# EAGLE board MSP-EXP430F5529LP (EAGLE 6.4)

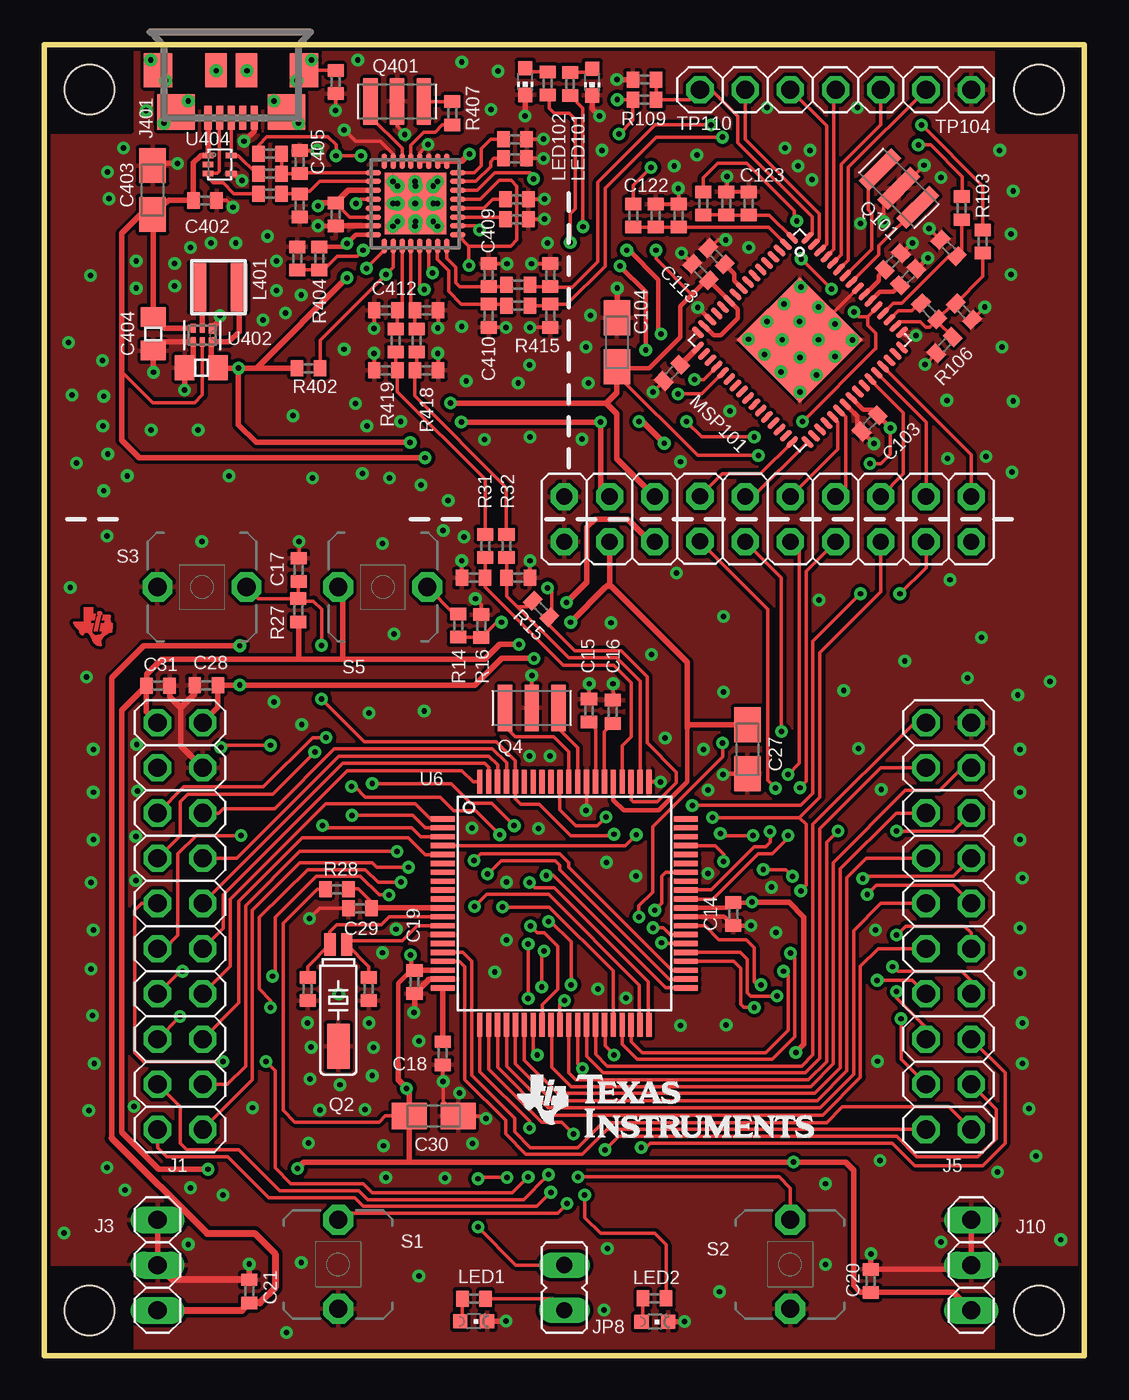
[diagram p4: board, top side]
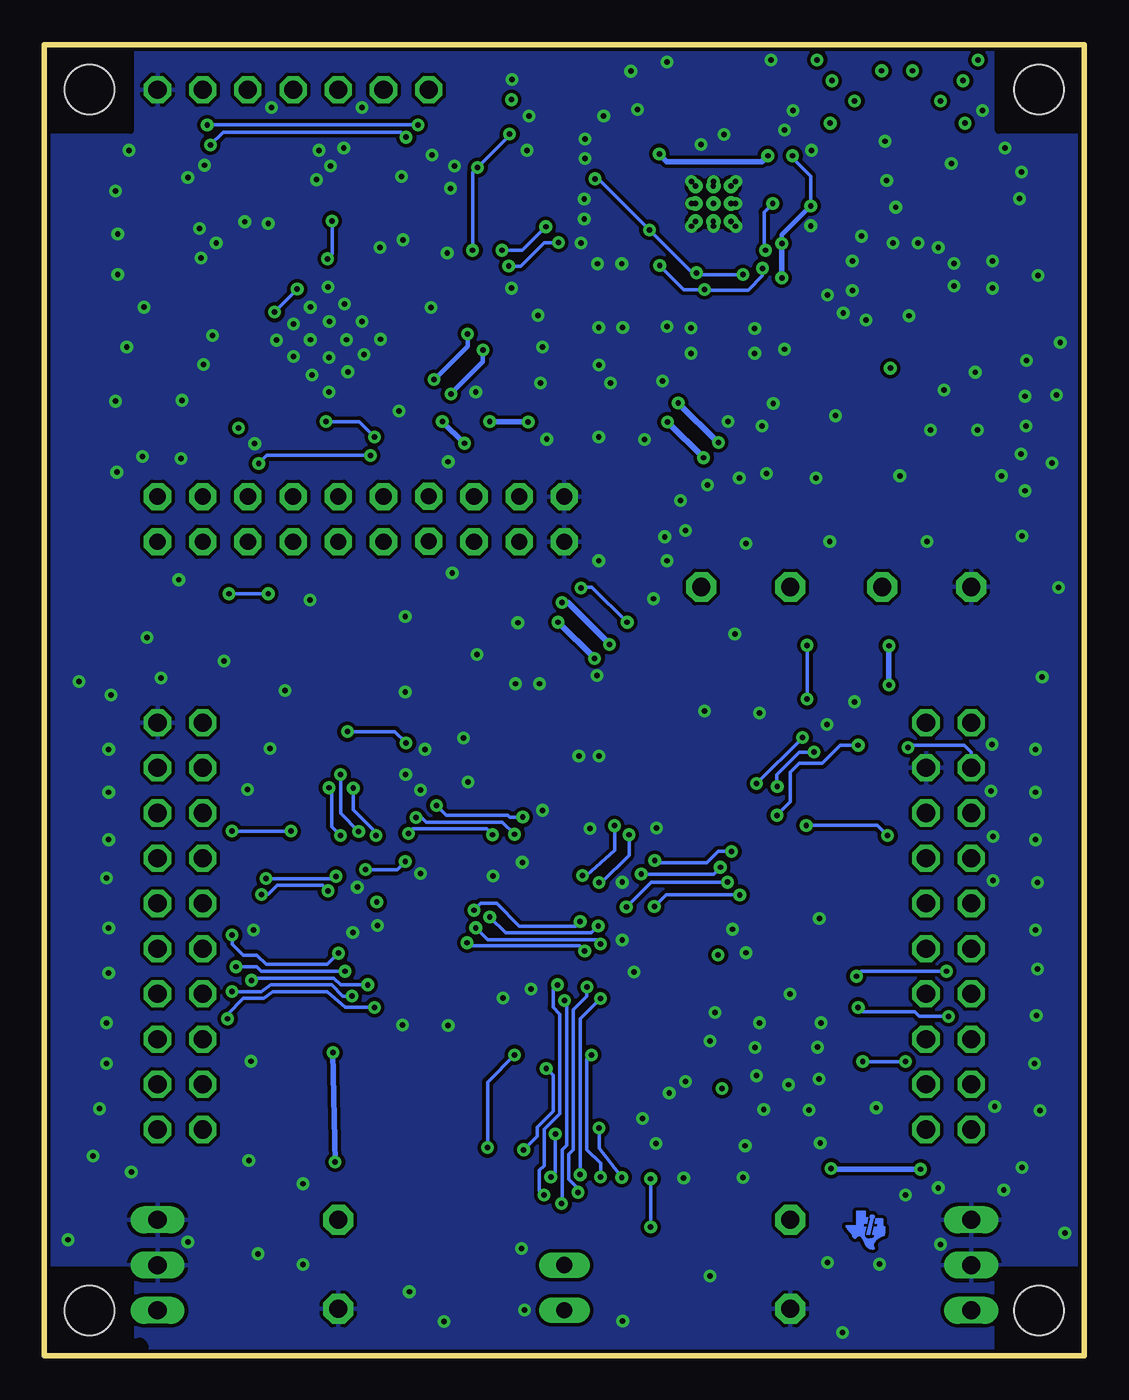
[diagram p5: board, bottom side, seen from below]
Size 58.42 x 73.66 mm. Coordinates in mm from the lower left corner, seen from the top.
Outline: 0,73.66 0,0 58.42,0 58.42,73.66 0,73.66
Copper layers (1*16): Top 0.0178mm / dielectric 12mil / Bottom 0.0178mm
Design rules "default": minimum track width 6mil, minimum drill 12mil, track to track 6mil, track to pad 6mil, pad to pad 6mil, via to via 8mil, smd to smd 6mil, copper to edge 8mil, drill to drill 8mil, minimum pad ring 10mil, minimum via ring 8mil, stop-mask expansion 8mil, vias tented up to drill 15mil, thermal gap 8mil
Net classes: 0 Default: width 0.203 mm, drill 0.305 mm, clearance 0.152 mm; 1 Ground: width 0.203 mm, drill 0.305 mm, clearance 0.152 mm to class 0, clearance 0.152 mm; 2 Power: width 0.203 mm, drill 0.305 mm, clearance 0.152 mm to class 0, clearance 0.152 mm to class 1, clearance 0.152 mm

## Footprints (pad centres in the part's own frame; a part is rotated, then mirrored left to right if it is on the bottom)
C0402 = smd 0.7 x 0.9: 1 -0.65,0; 2 0.65,0
A/3216-18R = smd 1.95 x 1.5: + 1.375,0; - -1.375,0
CSMD0805 = smd 1.092 x 1.397: 1 -0.94,0; 2 0.94,0
RHB_S-PQFP-N32 = smd 0.85 x 0.3: 1 -2.375,1.75; 2 -2.375,1.25; 3 -2.375,0.75; 4 -2.375,0.25; 5 -2.375,-0.25; 6 -2.375,-0.75; 7 -2.375,-1.25; 8 -2.375,-1.75; 17 2.375,-1.75; 18 2.375,-1.25; 19 2.375,-0.75; 20 2.375,-0.25; 21 2.375,0.25; 22 2.375,0.75; 23 2.375,1.25; 24 2.375,1.75 | smd 0.3 x 0.85: 9 -1.75,-2.375; 10 -1.25,-2.375; 11 -0.75,-2.375; 12 -0.25,-2.375; 13 0.25,-2.375; 14 0.75,-2.375; 15 1.25,-2.375; 16 1.75,-2.375; 25 1.75,2.375; 26 1.25,2.375; 27 0.75,2.375; 28 0.25,2.375; 29 -0.25,2.375; 30 -0.75,2.375; 31 -1.25,2.375; 32 -1.75,2.375 | smd 3.45 x 3.45: EXP 0,0 | drill 0.3 pad 0.6: EXP@1 -1,1; EXP@2 0,1; EXP@3 1,1; EXP@4 -1,0; EXP@5 0,0; EXP@6 1,0; EXP@7 -1,-1; EXP@8 0,-1; EXP@9 1,-1
2X10 = drill 1.016 octagon: 1 -11.43,-1.27; 2 -11.43,1.27; 3 -8.89,-1.27; 4 -8.89,1.27; 5 -6.35,-1.27; 6 -6.35,1.27; 7 -3.81,-1.27; 8 -3.81,1.27; 9 -1.27,-1.27; 10 -1.27,1.27; 11 1.27,-1.27; 12 1.27,1.27; 13 3.81,-1.27; 14 3.81,1.27; 15 6.35,-1.27; 16 6.35,1.27; 17 8.89,-1.27; 18 8.89,1.27; 19 11.43,-1.27; 20 11.43,1.27
1X03 = drill 1.016 long: 1 -2.54,0; 2 0,0; 3 2.54,0
HIROSE-ZX62R-B-5P = smd 1.35 x 0.4: D+ 2.675,0; D- 2.675,-0.65; GND 2.675,1.3; NC 2.675,0.65; VBUS 2.675,-1.3 | smd 1.9 x 1.6: SHIELD1 0,4.1; SHIELD2 0,-4.1 | smd 2 x 2.1: SHIELD3 2.35,3.1; SHIELD4 2.35,-3.1 | smd 1.9 x 1.2: SHIELD5 0,0.85; SHIELD6 0,-0.85
JP1M = drill 0.914 pad 1.524 octagon: 1 0,-1.27; 2 0,1.27
JP1 = drill 0.914 long: 1 0,-1.27; 2 0,1.27
L-NR3010 = smd 0.9 x 2.7: P$1 -1.15,0; P$2 1.15,0
CHIPLED_0603@1 = smd 0.8 x 0.8: A 0,-0.75; C 0,0.75
CHIP-LED0603 = smd 0.8 x 0.8: A 0,-0.75; C 0,0.75
RGC64 = smd 0.825 x 0.28: 1 -4.36,3.75; 2 -4.36,3.25; 3 -4.36,2.75; 4 -4.36,2.25; 5 -4.36,1.75; 6 -4.36,1.25; 7 -4.36,0.75; 8 -4.36,0.25; 9 -4.36,-0.25; 10 -4.36,-0.75; 11 -4.36,-1.25; 12 -4.36,-1.75; 13 -4.36,-2.25; 14 -4.36,-2.75; 15 -4.36,-3.25; 16 -4.36,-3.75; 33 4.36,-3.75; 34 4.36,-3.25; 35 4.36,-2.75; 36 4.36,-2.25; 37 4.36,-1.75; 38 4.36,-1.25; 39 4.36,-0.75; 40 4.36,-0.25; 41 4.36,0.25; 42 4.36,0.75; 43 4.36,1.25; 44 4.36,1.75; 45 4.36,2.25; 46 4.36,2.75; 47 4.36,3.25; 48 4.36,3.75 | smd 0.28 x 0.825: 17 -3.75,-4.36; 18 -3.25,-4.36; 19 -2.75,-4.36; 20 -2.25,-4.36; 21 -1.75,-4.36; 22 -1.25,-4.36; 23 -0.75,-4.36; 24 -0.25,-4.36; 25 0.25,-4.36; 26 0.75,-4.36; 27 1.25,-4.36; 28 1.75,-4.36; 29 2.25,-4.36; 30 2.75,-4.36; 31 3.25,-4.36; 32 3.75,-4.36; 49 3.75,4.36; 50 3.25,4.36; 51 2.75,4.36; 52 2.25,4.36; 53 1.75,4.36; 54 1.25,4.36; 55 0.75,4.36; 56 0.25,4.36; 57 -0.25,4.36; 58 -0.75,4.36; 59 -1.25,4.36; 60 -1.75,4.36; 61 -2.25,4.36; 62 -2.75,4.36; 63 -3.25,4.36; 64 -3.75,4.36 | smd 5 x 5: TP 0,0
MS3V-T1R = smd 0.635 x 1.27: P1 -0.47,-4.43; P2 0.47,-4.43 | smd 1.27 x 2.54: P3 0,1.3
MURATA-FILTER_CSTCR = smd 0.8 x 2.6: 1 -1.5,0; 2 0,0; 3 1.5,0
R0402 = smd 0.7 x 0.9: 1 -0.65,0; 2 0.65,0
PBTH = drill 1.016 pad 1.676 octagon: 1 -0.001,0.001; 2 5.001,0.001
MOUNTHOLE_110MIL = hole 2.794: 0,0
1X01 = drill 1.016 octagon: 1 0,0
PN80 = smd 1.35 x 0.3: 1 -6.825,4.75; 2 -6.825,4.25; 3 -6.825,3.75; 4 -6.825,3.25; 5 -6.825,2.75; 6 -6.825,2.25; 7 -6.825,1.75; 8 -6.825,1.25; 9 -6.825,0.75; 10 -6.825,0.25; 11 -6.825,-0.25; 12 -6.825,-0.75; 13 -6.825,-1.25; 14 -6.825,-1.75; 15 -6.825,-2.25; 16 -6.825,-2.75; 17 -6.825,-3.25; 18 -6.825,-3.75; 19 -6.825,-4.25; 20 -6.825,-4.75; 41 6.825,-4.75; 42 6.825,-4.25; 43 6.825,-3.75; 44 6.825,-3.25; 45 6.825,-2.75; 46 6.825,-2.25; 47 6.825,-1.75; 48 6.825,-1.25; 49 6.825,-0.75; 50 6.825,-0.25; 51 6.825,0.25; 52 6.825,0.75; 53 6.825,1.25; 54 6.825,1.75; 55 6.825,2.25; 56 6.825,2.75; 57 6.825,3.25; 58 6.825,3.75; 59 6.825,4.25; 60 6.825,4.75 | smd 0.3 x 1.35: 21 -4.75,-6.825; 22 -4.25,-6.825; 23 -3.75,-6.825; 24 -3.25,-6.825; 25 -2.75,-6.825; 26 -2.25,-6.825; 27 -1.75,-6.825; 28 -1.25,-6.825; 29 -0.75,-6.825; 30 -0.25,-6.825; 31 0.25,-6.825; 32 0.75,-6.825; 33 1.25,-6.825; 34 1.75,-6.825; 35 2.25,-6.825; 36 2.75,-6.825; 37 3.25,-6.825; 38 3.75,-6.825; 39 4.25,-6.825; 40 4.75,-6.825; 61 4.75,6.825; 62 4.25,6.825; 63 3.75,6.825; 64 3.25,6.825; 65 2.75,6.825; 66 2.25,6.825; 67 1.75,6.825; 68 1.25,6.825; 69 0.75,6.825; 70 0.25,6.825; 71 -0.25,6.825; 72 -0.75,6.825; 73 -1.25,6.825; 74 -1.75,6.825; 75 -2.25,6.825; 76 -2.75,6.825; 77 -3.25,6.825; 78 -3.75,6.825; 79 -4.25,6.825; 80 -4.75,6.825
DRY6 = smd 0.559 x 0.305: 1 -0.356,0.508 | smd 0.508 x 0.305: 2 -0.381,0; 3 -0.381,-0.508; 4 0.381,-0.508; 5 0.381,0; 6 0.381,0.508
TPD2E001-DRL = smd 0.3 x 0.6: 1 -0.5,-0.65; 2 0,-0.65; 3 0.5,-0.65; 4 0.5,0.65; 5 -0.5,0.65

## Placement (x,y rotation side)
C14  100n  [C0402]  38.7,24.8 270 top
C15  220n  [C0402]  30.59,36.23 90 top
C16  220n  [C0402]  31.94,36.17 90 top
C17  1n  [C0402]  14.27,44.15 90 top
C18  470n  [C0402]  22.39,16.98 90 top
C19  100n  [C0402]  20.79,20.98 90 top
C20  100n  [C0402]  46.43,4.19 90 top
C21  100n  [C0402]  11.51,3.61 90 top
C23  10p  [C0402]  26.62,43.69 0 top
C24  10p  [C0402]  24.1,43.69 180 top
C25  12p  [C0402]  18.22,20.59 90 top
C26  12p  [C0402]  14.78,20.59 90 top
C27  4u7  [A/3216-18R]  39.5,34.06 90 top
C28  100n  [C0402]  9.09,37.67 0 top
C29  100n  [C0402]  17.73,25.13 180 top
C30  10u  [A/3216-18R]  21.87,13.45 180 top
C31  100n  [C0402]  6.38,37.64 180 top
C101  470n  [C0402]  35.25,55.21 225 top
C102  220n  [C0402]  47.66,61.47 45 top
C103  100n  [C0402]  46.37,52.37 225 top
C104  10u  [A/3216-18R]  32.16,56.93 270 top
C107  220n  [C0402]  48.53,60.6 45 top
C110  10p  [C0402]  50.8,62.23 135 top
C111  10p  [C0402]  51.66,58.65 315 top
C112  1n  [C0402]  33.72,71.69 180 top
C113  100n  [C0402]  36.86,60.87 135 top
C121  100n  [C0402]  37.76,61.77 135 top
C122  33p  [C0402]  35.63,64.05 270 top
C123  33p  [C0402]  39.57,64.73 270 top
C401  1u  [CSMD0805]  8.81,55.5 0 top
C402  100n  [C0402]  9.02,64.9 0 top
C403  4u7  [A/3216-18R]  6.07,65.48 270 top
C404  1u  [CSMD0805]  6.11,57.4 90 top
C405  22p  [C0402]  14.35,67.06 90 top
C406  22p  [C0402]  14.35,64.62 270 top
C407  100n  [C0402]  16.36,64.11 270 top
C408  100n  [C0402]  14.2,61.65 90 top
C409  22p  [C0402]  24.97,60.71 90 top
C410  22p  [C0402]  24.97,58.42 270 top
C411  22p  [C0402]  21.46,58.72 0 top
C412  22p  [C0402]  19.18,58.72 180 top
DRAW1  [LOGO-ROCKET-10X7MM-BRD]  24.6,7.8 335 top
DRAW2  [LOGO-ROCKET-10X7MM-BRD]  3.08,56.8 65 top
IC401  TUSB2046BIRHBIRHB  [RHB_S-PQFP-N32]  20.84,64.72 0 top
J1  [2X10]  7.62,24.13 270 top
J3  PWR  [1X03]  6.35,5.08 270 top
J5  [2X10]  50.8,24.13 270 top
J10  PWR  [1X03]  52.07,5.08 270 top
J401  [HIROSE-ZX62R-B-5P]  10.49,72.21 270 top
JP1  +5V  [JP1M]  31.75,46.99 180 top
JP2  +3V3  [JP1M]  34.29,46.99 180 top
JP3  GND  [JP1M]  29.21,46.99 0 top
JP4.1  SBW_TST  [JP1M]  49.53,46.99 180 top
JP4.2  SBW_RST  [JP1M]  46.99,46.99 180 top
JP4.3  SBW_NC  [JP1M]  52.07,46.99 180 top
JP6.1  TXD  [JP1M]  44.45,46.99 180 top
JP6.2  RXD  [JP1M]  41.91,46.99 180 top
JP6.3  CTS  [JP1M]  39.37,46.99 180 top
JP6.4  RTS  [JP1M]  36.83,47.02 180 top
JP8  LED1_PWR  [JP1]  29.21,3.81 180 top
L401  2.2uH (NR3010T2R2M)  [L-NR3010]  9.78,60.02 0 top
LED1  [CHIPLED_0603@1]  24.12,1.92 270 top
LED2  [CHIPLED_0603@1]  34.29,1.89 270 top
LED101  red  [CHIP-LED0603]  30.77,71.55 180 top
LED102  green  [CHIP-LED0603]  27.01,71.58 180 top
MSP101  MSP430F5528IRGC  [RGC64]  42.44,57.06 315 top
Q2  32.768kHz  [MS3V-T1R]  16.51,18.67 180 top
Q4  CSTCR4M00G15L99  [MURATA-FILTER_CSTCR]  27.38,36.39 0 top
Q101  PIEZO_CSTCR4M00G15L99  [MURATA-FILTER_CSTCR]  48.01,65.58 135 top
Q401  CSTCR6M00G15L99  [MURATA-FILTER_CSTCR]  19.81,70.46 0 top
R14  100R  [R0402]  23.24,41.01 270 top
R15  1k4  [R0402]  27.9,41.95 135 top
R16  1M  [R0402]  24.54,40.98 270 top
R27  47k  [R0402]  14.26,41.87 270 top
R28  0R  [R0402]  16.43,26.2 180 top
R29  470R  [R0402]  24.13,3.2 180 top
R30  470R  [R0402]  34.28,3.21 180 top
R31  27R  [R0402]  24.76,45.49 270 top
R32  27R  [R0402]  25.96,45.49 270 top
R101  470  [R0402]  29.53,71.45 270 top
R102  390  [R0402]  28.27,71.48 270 top
R103  27R  [R0402]  51.54,64.47 270 top
R104  27R  [R0402]  52.73,62.59 270 top
R105  1k4  [R0402]  49.71,58.67 135 top
R106  1M  [R0402]  50.57,56.77 45 top
R109  47k  [R0402]  33.72,70.55 180 top
R121  220k  [R0402]  33.08,64.05 270 top
R122  220k  [R0402]  34.34,64.05 90 top
R124  240k  [R0402]  37.01,64.73 270 top
R125  150k  [R0402]  38.3,64.73 90 top
R401  33R  [R0402]  16.36,71.55 270 top
R402  10k  [R0402]  14.83,55.47 0 top
R403  1k5  [R0402]  12.67,67.51 0 top
R404  47k  [R0402]  15.44,61.65 270 top
R405  22R  [R0402]  12.67,66.4 180 top
R406  22R  [R0402]  12.67,65.28 180 top
R407  1k5  [R0402]  22.91,69.8 270 top
R408  15k  [R0402]  26.44,68.35 180 top
R409  15k  [R0402]  26.44,67.26 180 top
R410  22R  [R0402]  26.62,58.98 0 top
R411  22R  [R0402]  26.62,60.17 0 top
R412  15k  [R0402]  26.54,64.97 180 top
R413  15k  [R0402]  26.54,63.86 180 top
R414  15k  [R0402]  28.42,60.71 90 top
R415  15k  [R0402]  28.42,58.42 270 top
R416  22R  [R0402]  19.74,57.02 270 top
R417  22R  [R0402]  20.9,57.02 270 top
R418  15k  [R0402]  21.46,55.35 0 top
R419  15k  [R0402]  19.18,55.35 180 top
S1  [PBTH]  16.51,7.62 270 top
S2  [PBTH]  41.91,7.62 270 top
S3  RST  [PBTH]  6.35,43.18 0 top
S5  BSL  [PBTH]  16.51,43.18 0 top
STAND1  [MOUNTHOLE_110MIL]  2.54,2.54 0 top
STAND2  [MOUNTHOLE_110MIL]  55.88,2.54 0 top
STAND3  [MOUNTHOLE_110MIL]  55.88,71.12 0 top
STAND4  [MOUNTHOLE_110MIL]  2.54,71.12 0 top
TP104  TEST_PIN2  [1X01]  52.07,71.12 0 top
TP105  TEST_PIN2  [1X01]  49.53,71.12 0 top
TP106  TEST_PIN2  [1X01]  46.99,71.12 0 top
TP107  TEST_PIN2  [1X01]  44.45,71.12 0 top
TP108  TEST_PIN2  [1X01]  41.91,71.12 0 top
TP109  TEST_PIN2  [1X01]  39.37,71.12 0 top
TP110  TEST_PIN2  [1X01]  36.83,71.12 0 top
U6  MSP430F5529IPNR  [PN80]  29.21,25.4 0 top
U402  TPS62237DRY  [DRY6]  8.86,57.33 270 top
U404  TPD2E001DRLR  [TPD2E001-DRL]  9.84,66.92 270 top
U$1  [LOGO16_TPLACE]  26.48,12.08 0 top
U$2  [TILOGO_SMALL]  2.87,41.22 0 top
U$3  5529_REAR_SILK_REV1_5_FINAL  [5529_REAR_SILK_REV1_5_FINAL]  0,0 0 top
U$4  MS_TM  [MS_TM]  52.73,0.36 0 top
U$5  [TILOGO_SMALL]  12.14,7.32 0 bottom

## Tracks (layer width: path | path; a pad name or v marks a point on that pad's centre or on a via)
!OC  (via drill 0.3 pad 0.66)
  Top 0.203: IC401.14 21.59,61.03 v21.79,60.83 | IC401.10 19.59,61.15 v19.18,60.73 15.48,57.04 R402.2 | IC401.18 24.21,63.47 v24.43,63.25 | IC401.22 24.32,65.47 25.3,66.45 27.3,66.45 27.48,66.27 v27.48,66.12
  Bottom 0.203: v19.18,60.73 21.69,60.73 v21.79,60.83 22.02,60.83 v24.43,63.25 27.3,66.12 v27.48,66.12
!PWRON  (via drill 0.3 pad 0.66)
  Top 0.203: IC401.13 21.09,60.14 v21.34,59.89 | v23.85,61.24 23.85,62.33 | 23.85,62.33 IC401.17 23.85,62.33 | IC401.21 24.48,64.97 25.55,66.04 26.21,66.04 26.54,65.71 26.54,62.69 26.19,62.33 23.85,62.33 | IC401.9 19.09,62.09 v18.09,61.09
  Bottom 0.203: v23.85,61.24 22.5,59.89 v21.34,59.89 21.31,59.87 18.87,59.87 18.09,60.66 v18.09,61.09
+3V3  (via drill 0.3, 0.3 pad 0.66)
  Top 0.203: v39.75,25.48 39.78,25.48 | R28.2 15.33,26.2 13.41,24.28 13.41,13.77 14.07,13.11 18.8,13.11 19.15,13.46 20.99,13.46 C30.+ | 21,10.92 20.95,10.87
  Top 0.254: U6.50 38.39,25.15 C14.1 39.73,25.45 v39.75,25.48 | C31.2 5.74,37.66 | R27.2 14.28,41.21 | 19.86,16.38 19.86,20.9 20.61,21.65 | 20.81,21.65 20.61,21.65 | 20.61,21.65 20.61,22.47 v20.57,22.5
  Top 0.305: J1.1 5.72,36.19 C31.2 4.34,36.26 4.34,12.55 6.43,10.46 v9.2,10.46 | U6.18 20.81,21.65 C19.2 | 5.74,37.66 5.74,38.28 6.58,39.12 14.28,39.12 | 14.28,39.12 16.76,39.12 | 16.76,39.12 24.74,39.12 25.58,39.95 v26.67,39.95 | 14.28,41.21 14.28,39.12 | S5.1 16.76,42.92 16.76,39.12 | v39.75,25.48 41.83,25.48 42.67,24.64 42.67,17.48 v42.22,17.02 | 20.57,10.87 20.95,10.87 v42.09,10.87 45.01,10.87 45.47,10.41 45.47,3.94 45.85,3.56 46.42,3.56 C20.1 51.07,3.54 J10.3 | 20.57,10.87 14.58,10.87 v14.22,10.52 | 19.86,16.38 19.86,15.49 v20.34,15.01 20.49,14.86 C30.+ 20.49,10.95 20.57,10.87 | v29.34,42.32 30.48,43.46 30.48,46.53 30.94,46.99 32.77,46.99 34.04,45.72 JP2.2
  Bottom 0.305: v26.67,39.95 29.03,42.32 v29.34,42.32 | v9.2,10.46 13.89,10.46 v14.22,10.52 | v42.09,10.87 v42.22,17.02
+5V  (via drill 0.3 pad 0.66)
  Top 0.254: U6.65 31.96,31.21 32.54,30.63 34.52,30.63 36.12,32.23 36.12,35.28 36.28,35.44
  Top 0.305: J1.2 9.74,36.41 C28.2 v10.97,37.67 24.18,37.67 25.68,39.17 v27.51,39.17 | 36.12,35.28 36.12,38.94 31.84,43.22 31.65,43.22 31.52,43.16 | C27.+ 36.28,35.44 | v10.97,39.88 5.59,39.88 3.79,38.08 3.79,12.22 | 11.77,2.96 C21.1 | v29.57,41.2 31.52,43.16 | 31.52,43.16 31.75,43.38 JP1.2
  Top 0.406: 3.79,12.22 9.14,6.86 11.81,6.86 12.95,5.71 12.95,3.81 12.1,2.96 C21.1 11.09,2.54 J3.3
  Bottom 0.254: 29.54,41.2 v29.57,41.2
  Bottom 0.305: v27.51,39.17 29.54,41.2 | v10.97,39.88 v10.97,37.67
AVCC
  Top 0.203: C29.1 18.38,25.46 17.63,26.21 17.1,26.21 R28.1
  Top 0.305: U6.11 18.4,25.15 C29.1
EZFET_AVBUS
  Top 0.203: R124.2 | R124.2 R125.1 | R125.1 | R125.1 C123.2 40.73,64.08 MSP101.1
EZFET_AVCCOUT2ADC
  Top 0.203: R121.2 | R121.2 R122.1 C122.2 | C122.2 36.04,63.4 | MSP101.2 40.7,63.4 C122.2
EZFET_LED0  (via drill 0.3 pad 0.66)
  Top 0.203: R101.2 30.25,70.08 v30.25,63.42 | MSP101.20 37.04,54.84 v36.53,54.84
  Top 0.254: v32.72,62.1 32.84,62.1 34.49,60.45 34.49,57.56 v34.65,57.4
  Bottom 0.203: v30.25,63.42 31.57,62.1 v32.72,62.1
  Bottom 0.254: v34.65,57.4 34.65,56.72 v36.53,54.84
EZFET_LED1  (via drill 0.3 pad 0.66)
  Top 0.203: R102.2 28.37,70.73 28.37,70.08 28.65,69.8 29.49,69.8 29.82,69.47 29.82,64.44 29.54,64.16 v29.54,62.53 | MSP101.21 36.93,54.03 v35.59,54.03
  Top 0.254: v33.78,56.49 33.78,59.77 v32.33,61.21
  Bottom 0.203: v32.33,61.21 31.65,61.21 30.33,62.53 v29.54,62.53
  Bottom 0.254: v35.59,54.03 33.78,55.83 v33.78,56.49
EZFET_PU.0/DP
  Top 0.203: MSP101.50 48.07,58.09 49.2,58.09 49.51,57.78 49.73,57.78 R105.1 | R105.1 51.06,59.11 C111.1 52.73,60.63 R104.2 | R106.2 50.17,58.09 R105.1
EZFET_PU.1/DM
  Top 0.203: MSP101.52 47.7,59.13 48.16,59.13 50.8,61.77 C110.1 51.54,62.05 R103.2
EZFET_PUR
  Top 0.203: MSP101.51 47.97,58.7 48.72,58.7 49.15,59.13 R105.2
EZFET_RST
  Top 0.203: MSP101.64 43.13,63.05 43.13,63.98 38.96,68.15 38.96,69.62 37.47,71.12 TP110.1 36.26,70.55 R109.1 C112.1
EZFET_SBW_NC
  Top 0.203: MSP101.45 52.07,50.62 JP4.3.1
EZFET_SBW_RST
  Top 0.203: MSP101.43 46.41,54.83 48.26,52.98 48.26,49.53 JP4.2.1
EZFET_SBW_TST
  Top 0.203: MSP101.44 49.53,52.45 JP4.1.1
EZFET_TCK
  Top 0.203: MSP101.63 43.54,62.75 43.54,64.16 39.37,68.33 TP109.1
EZFET_TDI
  Top 0.203: MSP101.61 44.35,62.15 44.35,71.02 TP107.1
EZFET_TDO
  Top 0.203: MSP101.60 44.76,61.85 44.76,66.93 46.99,69.16 TP106.1
EZFET_TEST
  Top 0.203: MSP101.59 45.16,61.55 45.16,66.75 TP105.1
EZFET_TMS
  Top 0.203: MSP101.62 43.94,62.45 43.94,69.09 TP108.1
EZFET_UARTCTS
  Top 0.203: MSP101.32 40.21,49.53 38.08,49.53 JP6.4.1
EZFET_UARTRTS
  Top 0.203: MSP101.33 39.81,48.26 JP6.3.1
EZFET_UARTRXD
  Top 0.203: MSP101.38 44.67,53.09 45.01,52.76 45.01,48.82 JP6.1.1
EZFET_UARTTXD
  Top 0.203: MSP101.37 44.58,52.45 44.58,50.93 JP6.2.1
EZFET_V18
  Top 0.254: MSP101.55 46.08,59.61 46.86,60.4 46.86,60.67 C102.1
EZFET_VBUS  (via drill 0.3 pad 0.66)
  Top 0.203: R124.1 37.01,66.17 37.82,66.98 39.47,66.98 42.14,64.31 42.14,63.88 v42.27,63.75 | MSP101.53 46.76,58.88 46.25,58.37 | 46.25,58.37 45.75,58.37 v45.49,58.62 | v42.52,61.62 v44.22,59.92 | 46.25,58.37 46.25,57.89 46.71,57.43 46.71,56.57 46.69,56.57 v42.6,52.48 | v39.88,51.61 36.93,51.61 v36.07,52.48 | J401.VBUS | 8.87,54.61 U402.5 8.87,53.98 8.43,53.54 6.07,53.54 4.34,55.27
  Top 0.305: v21.39,50.44 5.33,50.44 4.34,51.44 4.34,55.27 4.34,63.07 5.38,64.11 C403.+ | v23.42,52.45 v31.24,52.45 31.24,48.77 JP1.1 | v33.4,52.48 33.6,52.48 v34.82,51.26 | C403.+ 6.99,64.9 C402.1 8.36,65.03 8.36,67 8.77,67.42 U404.1 J401.VBUS | U402.3 6.74,57.71 C404.2 6.11,64.07 C403.+
  Bottom 0.203: v42.27,63.75 42.27,61.9 42.52,61.65 | 42.52,61.65 v42.52,61.62 | 44.22,59.89 v44.22,59.92 45.49,58.65 v45.49,58.62 | v42.6,52.48 40.74,52.48 v39.88,51.61 | 42.49,61.65 42.52,61.65
  Bottom 0.305: v21.39,50.44 23.39,52.45 v23.42,52.45 | v34.82,51.26 34.85,51.26 v36.07,52.48 | v33.4,52.48 31.24,52.48 v31.24,52.45
EZFET_VCC  (via drill 0.3 pad 0.66)
  Top 0.203: v32.18,70.56 33.05,70.56 R109.2 33.06,69.41 v32.28,68.63 | v46.38,50.11 46.99,50.11 47.52,50.65 v47.52,52.12 | C104.+ 32.22,55.05 36.7,50.57 v40.11,50.57 | R121.1 33.08,65.75 v34.09,66.75 | v34.37,62.1 34.37,61.62 36.37,59.61 | v17.78,67.41 v16.38,67.41 16.38,68.02 15.93,68.48 12.5,68.48 12.03,68.01 R403.1 | IC401.6 17.15,63.97 C407.1
  Top 0.254: MSP101.15 37.07,57.85 37.59,57.33 38,57.33 38.94,58.27 38.94,58.8 MSP101.11 C113.1 37.17,60.41 36.37,59.61 35.71,58.95 35.71,57.2 33.98,55.47 32.25,55.47 C104.+ | v47.52,52.12 46.83,52.82 C103.1 46.53,53.14 46,53.14 45.35,53.79 MSP101.40 | IC401.8 17.48,62.97 v16.99,62.48 16.8,62.3 R404.1
  Top 0.305: 20.54,51.3 v20.55,51.31 11.89,51.31 10.9,52.3 v10.9,55.47 | v22.81,53.52 31.57,53.52 | C104.+ 32.16,54.11 31.57,53.52 | 31.57,53.52 32.16,52.93 32.16,50.39 JP2.1 | L401.P$2 10.93,57.51 10.36,56.95 U402.6 9.37,56.29 9.37,55.88 C401.2 9.78,55.47 v10.9,55.47 | IC401.25 IC401.26 23.46,67.09 v23.88,67.51 | v10.9,55.47 11.91,55.47 | 11.91,55.47 v16.99,60.55 | IC401.3 17.07,65.47 C407.1 15.53,64.76 v15.37,64.59 | R402.1 11.91,55.47
  Bottom 0.203: v46.38,50.11 45.92,50.57 v40.11,50.57 | v32.28,68.63 32.28,68.56 v34.09,66.75 34.37,66.47 v34.37,62.1 | v15.37,64.59 15.37,66.27 16.38,67.28 v16.38,67.41
  Bottom 0.254: v16.99,62.48 16.99,62.97 v15.37,64.59
  Bottom 0.305: v20.55,51.31 20.6,51.31 v22.81,53.52 | v23.88,67.51 23.44,67.08 18.11,67.08 v17.78,67.41 | v16.99,60.55 v16.99,62.48
EZFET_VREF
  Top 0.254: MSP101.9 38.76,60.4 38.76,60.77 C121.1
EZFET_VUSB
  Top 0.254: MSP101.54 46.43,59.26 46.94,59.77 47.69,59.77 C107.1
EZFET_XT2IN
  Top 0.203: MSP101.57 46.89,61.85 46.89,62.34 Q101.1
EZFET_XT2OUT
  Top 0.203: MSP101.58 46.48,62.15 46.48,64.16 46.28,64.36 46.28,65.98 Q101.3
GND  (via drill 0.3 pad 0.66)
  Top 0.203: C405.2 15.15,67.71 v15.32,67.72 | C412.2 v18.53,57.72 v18.52,57.71 | C411.2 22.11,57.75 v22.1,57.73 | R418.2 22.11,56.3 v22.1,56.31 | R419.2 18.53,56.22 v18.52,56.31 | U6.61 v34.62,32.23 | C16.2 31.98,36.86 v31.95,37.74 | C15.2 30.61,36.9 v30.61,37.74 | U6.68 30.46,30.66 v30.43,30.63 | Q4.2 v27.38,38.2 | C24.2 23.45,44.41 v23.44,44.65 | C23.2 27.27,44.41 v27.28,44.65 | R16.1 24.54,42.19 v24.21,42.52 | C17.2 14.3,44.82 v14.3,45.74 | C18.1 22.39,15.58 v22.4,15.39 22.4,14.29 C30.- 24.68,13.45 v24.82,13.31 | C110.2 49.84,63.2 v49.71,63.32 | C111.2 52.76,58.82 v52.83,58.9 | MSP101.49 48.37,57.3 v48.97,57.3 | R106.1 v49.48,55.68 | 37.39,62.23 37.85,62.69 v38.28,62.69 | C123.1 R125.2 38.35,65.43 v38.35,66.24 | 34.37,64.72 R122.2 C122.1 35.63,65.49 v35.61,65.58 | C101.2 34.2,54.15 v34.19,54.13 | MSP101.56 44.07,58.34 | v49.43,66.88 48.13,65.58 Q101.2 47.17,64.75 v47.17,63.7 | R408.1 v28.04,68.35 | R409.1 v28.04,67.26 | R413.1 v28.09,63.86 | R412.1 v28.09,64.97 | C409.2 25.97,61.36 v25.98,61.34 | R414.2 27.37,61.36 v27.36,61.34 | R415.2 v27.29,57.77 v27.28,57.76 | C410.2 v25.92,57.77 v25.93,57.76 | R401.2 v16.36,69.95 | IC401.27 IC401.28 21.09,67.55 v21.54,68.05 | Q401.2 19.81,69.09 v20.24,68.61 | C29.2 15.46,25.13 v14.88,24.56 | C402.2 10.21,64.9 v10.59,64.52 | IC401.31 19.59,67.51 18.87,68.22 17.47,68.22 v16.84,68.86
  Top 0.254: MSP101.14 37.42,58.22 v36.7,58.88 | C121.2 37.39,62.23 | C113.2 36.4,61.36 v35.79,61.95 | v46.61,51.23 45.93,51.91 C103.2 45.67,52.15 45.67,52.78 MSP101.39 | C107.2 49.02,61.06 v49.63,61.67 | C102.2 48.19,61.93 v48.77,62.51 | C27.- 38.17,32.69 v38.12,32.64 | U6.49 38.2,24.65 C14.2 39.67,24.15 v39.7,24.16
  Top 0.305: U404.4 10.55,66.42 v11.1,66.02 | J401.GND 11.79,68.79 v11.2,68.22 | C403.- 6.19,66.98 v7.47,66.98 | U402.1 9.83,58.14 v9.86,58.42 | v7.87,54.25 C401.1 8.36,55.98 U402.4 6.59,56.95 C404.1 6.12,56.45 v6.12,55.24 | C104.- 32.18,57.82 v32.18,59.97 | LED102.C v27.01,69.66 v27,69.65 | LED101.C 30.77,70.07 v31.19,69.65 | C112.2 v32.17,71.69 v32.16,71.7 | C31.1 7.03,37.02 7.64,36.4 | 7.64,36.4 7.64,34.27 J1.4 | C28.1 8.44,37.2 7.64,36.4 | J10.1 J10.2 51.83,4.84 C20.2 v46.43,5.71 | C21.2 v11.51,5.13 | J3.2 J3.1 | LED1.C 25.92,1.92 v25.93,1.93 | LED2.C 35.93,1.89 35.94,1.91 v35.97,1.91 | U6.19 21.61,21.15 C19.1 20.79,19.32 v20.75,19.28 | v15.37,63.48 C407.2 IC401.7 | v44.43,57.96 44.2,57.96 43.54,58.62 43.79,58.62 44.07,58.34
  Top 0.406: C21.2 7.17,4.26 J3.2
  other vias: 18.24,18.69 14.78,18.69 42.49,60.05 39.55,57.1 41.38,55.27 45.39,57.05 43.48,58.9 41.55,59.08 40.59,58.09 42.42,58.09 41.45,57.07 40.46,56.24 42.44,54.13 43.38,55.09 44.42,56.13 43.48,57.07 42.44,56.08 45.85,63.6 2.36,38.13 1.45,43.15 3.33,48.59 8.84,45.75 19,45.62 19.63,40.54 46.94,10.95 14.45,35.46 18.24,36.09 21.34,36.22 28.4,33.68 24.03,29.64 27.76,29.62 25.96,26.59 41.1,23.77 33.22,26.95 34.87,34.7 31.83,41.17 35.51,43.97 45.75,34.11 51.87,38.07 37.29,31.78 38.15,41.53 38.15,37.29 44.91,37.36 43.51,42.44 50.88,43.59 48.34,39.01 47.02,31.8 54.69,37.11 54.36,49.63 50.7,53.67 54.43,53.62 53.8,56.67 54.31,60.73 54.43,65.43 53.67,67.72 54.31,63.02 50.37,66.19 43.13,66.07 43,67.72 41.61,67.84 36.65,67.46 35.38,66.83 39.57,62.26 42.34,66.83 40.59,70.13 45.67,70.13 25.48,72.16 25.1,70 28.27,62.51 30.43,56.67 31.32,67.72 30.68,58.45 26.62,54.64 27.25,55.65 23.44,57.81 23.7,54.76 27.28,51.61 24.71,51.46 50.75,50.39 21.16,48.92 22.68,48.03 30.56,54.64 23.57,46 22.4,46.35 19.38,49.3 17.86,49.56 18.11,52.22 20.02,52.48 17.48,53.49 16.84,56.54 14.43,59.59 13.54,58.57 12.27,58.19 13.03,59.84 13.03,61.49 12.52,62.89 10.74,62.51 9.35,62.51 8.2,62.26 7.32,61.37 7.32,60.1 23.44,72.67 17.6,72.8 5.16,61.49 5.16,59.97 5.71,69.95 1.55,53.98 1.35,56.92 4.45,67.84 3.53,66.5 1.8,50.14 2.59,60.68 3.63,65 3.25,55.91 3.33,53.9 3.28,52.22 3.56,50.65 4.65,49.43 10.36,49.43 15.06,49.3 2.74,34.06 3.51,46.05 2.74,31.65 2.74,28.98 2.62,26.57 2.74,23.9 2.62,21.72 2.69,19.1 2.79,16.41 2.49,13.77 3.51,10.57 4.52,9.3 10.03,9.02 22.5,9.98 50.37,6.38 53.54,10.31 55.7,11.2 55.32,13.87 54.94,16.41 54.94,18.69 54.81,21.49 54.81,24.03 54.94,26.82 54.81,28.98 54.81,31.65 54.81,34.06 46.81,16.54 37.29,27.08 40.84,26.31 38.3,18.57 31.57,27.71 31.09,20.6 52.65,40.34 24.05,11.91 32.66,20.09 25.3,21.54 25.96,23.34 35.74,18.54 46.69,23.9 21.03,17.68 23.32,14.76 18.01,13.82 21.03,4.47 13.59,1.3 31.45,2.57 37.92,3.58 31.62,6.02 43.89,5.11 12.9,36.73 57.1,6.5 1.09,6.88 16.61,15.21 14.91,15.54 18.41,15.72 18.49,17.3 16.54,20.32 14.99,17.32 19,22.63 27.25,33.68 5.23,31.72 34.11,39.4 37.03,34.06 19.18,10.01 19.58,64.72 22.07,64.72 20.83,64.72 19.58,65.96 22.07,65.96 20.83,65.96 19.58,63.45 22.07,63.45 20.83,63.45 43.89,9.65 35.74,50.22 38.51,53.06 52.91,50.52 30.2,51.49 56.49,37.87 5.18,34.34 5.13,29.16 5.13,26.7 14.83,11.94 11.68,13.92 5.03,14 19.76,23.95 15.47,13.79 19.05,11.79 5.99,51.99 8.64,51.99 13.97,52.81 8.08,6.25 14.43,5.23 8.2,9.42
  pour Top (isolate 0.203, rank 2): -3.02,75.64 -2.57,-2.39 59.94,-0.25 61.62,76.28
  pour Bottom (isolate 0.203, rank 2): -1.32,76.71 -7.14,-2.18 63.25,0 63.14,74.3
  pour Top (isolate 0.203): 23.39,25.15 14.61,25.15 13.82,24.38 13.79,15.52 14.71,14.55 18.44,14.55 19.38,15.47 19.38,22.28 20.75,23.65 23.39,23.65
  pour Top (isolate 0.203): 22.43,71.68 21.67,72.44 18.08,72.44 17.42,71.78 17.42,68.99 19.18,66.67 21.64,66.62 22.07,68.07 22.07,68.28 23.65,68.28 23.65,71.73
  pour Top (isolate 0.203): 30.48,31.24 30.51,34.54 29.92,35.13 29.9,37.67 29.13,38.43 25.55,38.43 24.89,37.77 24.89,34.98 25.63,34.24 28.63,34.24 28.93,33.93 28.93,31.24
HUB_DM1
  Top 0.203: R416.2 19.74,55.44 R419.1 19.83,54.16 24.76,49.23 R31.1
HUB_DM2  (via drill 0.3 pad 0.66)
  Top 0.203: R103.1 51.56,65.14 51.56,66.24 49.78,68.02 v49.1,68.02 | v38.1,68.45 34.37,68.45 31.5,65.58 31.5,61.21 29.35,59.07 R415.1 28.33,58.98 R410.2
  Bottom 0.203: v49.1,68.02 48.39,68.73 38.38,68.73 v38.1,68.45
HUB_DP1
  Top 0.203: R417.2 20.9,55.44 R418.1 20.81,53.91 25.96,48.77 R32.1
HUB_DP2  (via drill 0.3 pad 0.66)
  Top 0.203: R104.1 52.73,65.71 49.3,69.14 v49.28,69.14 | v37.44,69.14 34.31,69.14 31.09,65.91 31.09,61.44 29.67,60.02 28.46,60.02 R414.1 27.39,60.06 R411.2
  Bottom 0.203: v37.44,69.14 v49.28,69.14
N$1
  Top 0.203: 29.58,72.05 R101.1 30.57,72.1 LED101.A
N$2
  Top 0.203: LED102.A 27.06,72.13 R102.1
N$3
  Top 0.203: IC401.15 22.07,62.33 22.07,61.59 22.71,60.96 22.71,59.79 23.43,59.07 C410.1 25.88,59.07 R410.1
N$4
  Top 0.203: R14.1 23.03,41.66 S5.2
N$5
  Top 0.203: R403.2 R405.1 14.34,66.4 C405.1 14.41,66.47 IC401.1
N$6
  Top 0.203: IC401.30 20.09,67.82 18.31,69.6 Q401.1
N$7
  Top 0.203: R29.1 28.55,3.2 JP8.2
N$8
  Top 0.305: MSP101.17 35.73,55.65 C101.1
N$9  (via drill 0.3 pad 0.3)
  other vias: 6.71,69.24
N$10
  Top 0.203: R401.1 14.6,72.2 J401.SHIELD1
N$11
  Top 0.203: R406.1 C406.1 14.49,65.41 14.91,65.41 15.47,65.97 IC401.2
N$12
  Top 0.203: J401.D+ U404.5 10.89,67.42 11.91,66.4 R405.2
N$13
  Top 0.203: J401.D- 9.83,69.53 9.83,66.55 9.7,66.42 U404.3 9.19,66.17 9.47,65.89 10.03,65.89 10.64,65.28 R406.2
N$14
  Top 0.305: U402.2 8.87,58.9 8.63,59.14 L401.P$1
N$15
  Top 0.203: R407.2 22.36,69.15 21.95,68.73 21.31,68.73 20.59,68.01 IC401.29
N$16
  Top 0.203: IC401.11 20.09,58.99 C412.1 19.83,57.76 R416.1
N$17
  Top 0.203: IC401.12 20.59,58.95 C411.1 20.81,57.76 R417.1
N$18
  Top 0.203: IC401.16 22.61,62.33 22.61,61.65 23.11,61.14 23.11,60.27 23.33,60.06 C409.1 25.85,60.06 R411.1
N$19  (via drill 0.3 pad 0.66)
  Top 0.203: IC401.4 17.75,64.97 v17.5,64.72 | C408.1 R404.2 15.68,61 16.46,61.77 17.58,61.77 v17.91,62.1
  Bottom 0.203: v17.5,64.72 17.98,64.24 17.98,62.18 v17.91,62.1
N$20
  Top 0.203: R412.2 25.2,64.97 24.69,64.47 IC401.20
N$21
  Top 0.203: IC401.24 24.15,66.47 24.54,66.85 24.54,67.82 25.07,68.35 R408.2
N$22
  Top 0.203: IC401.23 24.24,65.97 25.07,66.8 25.07,67.08 25.25,67.26 R409.2
N$23
  Top 0.203: IC401.19 25.75,63.97 R413.2
N$24  (via drill 0.3 pad 0.3)
  other vias: 8.08,70.48
N$25  (via drill 0.3 pad 0.3)
  other vias: 12.9,70.48
N$26  (via drill 0.3 pad 0.3)
  other vias: 14.27,69.24
N$27  (via drill 0.3 pad 0.3)
  other vias: 15.01,72.8
N$28
  Top 0.203: R407.1 21.32,70.45 Q401.3
N$29  (via drill 0.3 pad 0.3)
  other vias: 14.17,71.63
N$30  (via drill 0.3 pad 0.3)
  other vias: 6.81,71.63
N$31  (via drill 0.3 pad 0.3)
  other vias: 5.97,72.8
N$32
  Top 0.203: LED1.A 23.48,2.03 R29.2
N$33  (via drill 0.3 pad 0.3)
  other vias: 9.65,72.19
N$34  (via drill 0.3 pad 0.3)
  other vias: 11.38,72.19
N$35
  Top 0.203: LED2.A 33.63,1.98 R30.2
P1.0  (via drill 0.3 pad 0.3)
  Top 0.203: U6.21 24.46,15.95 27.25,13.16 v27.25,12.78 | U6.21 | v24.36,7.21 26.49,5.08 JP8.1 | v25.98,10.01 24.43,10.01 v24.36,9.93
  Bottom 0.203: v24.36,9.93 v24.36,7.21 | v25.98,10.01 27.25,11.66 v27.25,12.78
P1.1  (via drill 0.3)
  Top 0.203: U6.22 24.96,16.09 27.94,13.11 29.06,13.11 v29.72,12.45 | v29.97,10.03 41.28,10.03 41.91,9.4 S2.1
  Bottom 0.203: v29.72,12.45 29.72,10.29 v29.97,10.03
P1.2
  Top 0.203: U6.23 25.46,16.2 28.14,13.51 43.72,13.51 45.85,15.64 45.85,21.87 46.84,22.86 J5.11
P1.3
  Top 0.203: U6.24 25.96,16.25 28.3,13.92 43.59,13.92 45.47,15.79 45.47,23.86 47,25.4 J5.9
P1.4
  Top 0.203: U6.25 26.46,16.39 28.52,14.33 43.41,14.33 45.09,16 45.09,26.85 46.18,27.94 J5.7
P1.5
  Top 0.203: U6.26 26.96,16.6 28.83,14.73 43.27,14.73 44.7,16.17 44.7,27.34 47.85,30.48 J5.5
P1.6  (via drill 0.3)
  Top 0.203: U6.27 27.46,17.12 v27.69,16.89 | 26.92,9.78 v27.18,10.03 26.29,9.14 18.41,9.14 17.91,9.65 13.84,9.65 12.95,10.54 12.95,16 v12.45,16.51 | v10.03,16.51 5.59,16.51 5.08,17.02 5.08,25.02 5.46,25.4 J1.9
  Bottom 0.203: v12.45,16.51 v10.03,16.51 | v27.69,16.89 27.94,16.64 27.94,11.56 27.18,10.79 v27.18,10.03
P1.7  (via drill 0.3)
  Top 0.203: U6.28 27.96,19.7 28.83,20.57 28.83,22.99 28.07,23.75 27.69,23.75 v27.3,24.13 | v38.1,34.42 38.1,33.66 34.16,29.72 34.16,26.04 33.4,25.27 v33.4,24.64 | v41.4,35.05 41.4,43.69 JP6.3.2
  Bottom 0.203: v38.1,34.42 38.73,35.05 v41.4,35.05 | v27.3,24.13 27.69,23.75 32.51,23.75 v33.4,24.64
P2.0
  Top 0.203: U6.29 28.5,18.54 28.5,16.2 29.59,15.11 43.05,15.11 44.32,16.38 44.32,27.7 48.37,31.75 50.29,31.75 50.93,32.38 51.56,33.02 J5.4
P2.1  (via drill 0.3, 0.3 pad 0.66)
  Top 0.203: U6.30 28.96,19.76 29.14,19.94 v29.21,19.94 | S1.1 16.69,7.62 17.07,8 28.83,8 v29.36,8.53
  Bottom 0.203: v29.21,19.94 29.08,19.81 29.08,11.81 29.34,11.56 29.34,8.56 v29.36,8.53
P2.2  (via drill 0.3)
  Top 0.203: U6.31 29.46,15.88 29.84,15.49 42.92,15.49 43.94,16.52 43.94,28.83 v44.58,29.46 | v47.88,29.46 51.05,29.46 J5.6
  Bottom 0.203: v47.88,29.46 v44.58,29.46
P2.3  (via drill 0.3)
  Top 0.203: U6.32 29.97,18.56 29.97,16.38 v30.23,16.13 | J5.18 53.47,13.84 53.47,12.19 52.45,11.18 49.02,11.18 47.88,12.32 32.26,12.32 v31.5,11.56
  Bottom 0.203: v30.23,16.13 29.84,15.75 29.84,13.72 30.73,12.83 30.73,12.32 v31.5,11.56
P2.4
  Top 0.203: U6.33 30.46,16.81 31.39,15.88 42.75,15.88 43.56,16.69 43.56,29.6 46.98,33.02 J5.3
P2.5
  Top 0.203: U6.34 30.96,16.91 31.62,16.26 42.55,16.26 43.18,16.89 43.18,29.84 48.9,35.56 J5.1
P2.6  (via drill 0.3)
  Top 0.203: U6.35 31.5,18.54 31.5,17.4 v32,16.89 | J5.16 53.98,15.88 53.98,11.94 52.71,10.67 48.9,10.67 47.62,11.94 34.04,11.94 33.78,11.68 v33.53,11.68
  Bottom 0.203: v32,16.89 33.53,15.37 v33.53,11.68
P2.7  (via drill 0.3 pad 0.66)
  Top 0.203: 31.95,18.58 U6.36 31.96,21.61 28.37,25.2 v25.73,25.2 | v12.7,19.56 12.7,19.94 12.07,20.6 12.07,24.61 14.78,27.3 18.03,27.3 18.75,26.59 v20.04,26.59 | v7.62,19.05 J1.15
  Bottom 0.203: v12.7,19.56 12.45,19.3 9.53,19.3 9.27,19.05 v7.62,19.05 | v20.04,26.59 24.33,26.59 v25.73,25.2
P3.0  (via drill 0.3)
  Top 0.203: U6.37 32.46,17.49 33.31,16.64 40.89,16.64 42.16,17.91 42.16,22.35 v41.91,22.61 | J5.12 52.07,23.75 51.69,24.13 48.39,24.13 v47.88,23.62
  Bottom 0.203: v41.91,22.61 42.55,21.97 45.97,21.97 46.48,22.48 47.24,22.48 47.88,23.11 v47.88,23.62
P3.1  (via drill 0.3)
  Top 0.203: U6.38 32.97,17.63 33.58,17.02 40.51,17.02 41.78,18.29 41.78,21.34 v41.53,21.59 | J5.14 52.07,21.05 51.53,21.59 47.93,21.59 v47.65,21.84
  Bottom 0.203: v41.53,21.59 46.23,21.59 46.48,21.84 v47.65,21.84
P3.2  (via drill 0.3 pad 0.66)
  Top 0.203: U6.39 33.43,18.61 33.43,20.8 28.32,25.91 24.84,25.91 v24.15,25.22 | v12.8,21.31 12.95,21.46 12.95,24.61 15.27,26.92 17.75,26.92 18.8,25.88 v19.36,25.88 | v7.75,21.59 7.62,21.59 J1.13
  Bottom 0.203: v7.75,21.59 12.52,21.59 v12.8,21.31 | v19.36,25.88 23.49,25.88 v24.15,25.22
P3.3  (via drill 0.3 pad 0.3, 0.3 pad 0.66)
  Top 0.203: U6.40 33.93,18.6 33.93,21.01 28.65,26.29 27.53,26.29 v27.25,26.57 | v25.58,29.26 24.23,30.61 22.99,30.61 22.22,31.37 18.03,31.37 17.42,31.98 v17.25,31.98 | v15.19,33.91 12.83,31.55 8.05,31.55 7.62,31.11 7.62,29.21 J1.7
  Bottom 0.203: v25.58,29.26 25.58,28.12 27.13,26.57 v27.25,26.57 | v15.19,33.91 16,33.91 17.27,32.64 17.27,32 v17.25,31.98
P3.4  (via drill 0.3 pad 0.3, 0.3 pad 0.66)
  Top 0.203: U6.41 34.9,20.65 28.57,26.98 v28.19,26.98 | v18.41,32.13 22.86,32.13 23.95,31.04 25.12,31.04 v26.39,29.77 | v15.82,34.72 15.06,34.72 12.29,31.95 7.82,31.95 J1.5
  Bottom 0.203: v26.39,29.77 26.39,28.4 27.94,26.98 v28.19,26.98 | v18.41,32.13 v15.82,34.72
P3.5  (via drill 0.3)
  Top 0.203: U6.42 35.11,21.15 28.96,27.3 28.96,27.56 28.7,27.81 25.65,27.81 v24.89,27.05 | J1.20 11.68,15.49 11.68,25.02 14.35,27.69 18.41,27.69 18.67,27.43 v20.45,27.43
  Bottom 0.203: v24.89,27.05 20.83,27.05 v20.45,27.43
P3.6  (via drill 0.3)
  Top 0.203: U6.43 35.25,21.65 29.46,27.43 29.46,27.69 28.96,28.19 24.51,28.19 v24.13,27.81 | J1.18 10.28,15.24 11.3,16.26 11.3,25.27 14.35,28.32 v19.81,28.32
  Bottom 0.203: v24.13,27.81 24,27.69 21.21,27.69 20.57,28.32 v19.81,28.32
P3.7  (via drill 0.3)
  Top 0.203: U6.44 38.72,22.15 39.12,21.75 39.12,19.74 39.3,19.56 v39.88,19.56 | J5.17 48.13,16.64 v48.13,18.92
  Bottom 0.203: v39.88,19.56 41.53,19.56 42.55,20.45 45.59,20.45 46.1,20.07 47.24,20.07 48.13,19.18 v48.13,18.92
P4.0  (via drill 0.3)
  Top 0.203: U6.45 39.11,22.65 39.5,22.26 39.5,20.37 39.68,20.19 v41.15,20.19 | v47.88,20.45 47.88,20.07 49.53,18.41 J5.15
  Bottom 0.203: v41.15,20.19 41.66,20.19 42.29,20.83 45.72,20.83 46.23,20.45 v47.88,20.45
P4.1  (via drill 0.3 pad 0.66)
  Top 0.203: v27.94,20.7 27.94,22.58 v28.07,22.73 | 28.14,8.87 v28.45,9.17 27.66,8.38 17.91,8.38 17.42,8.87 12.6,8.87 10.29,11.18 6.86,11.18 6.35,11.68 J1.19 | U6.46 34.71,23.15 v34.67,23.19
  Bottom 0.203: v28.07,22.73 28.35,23.01 34.49,23.01 v34.67,23.19 | 27.94,20.32 v27.94,20.7 27.94,20.19 28.7,19.43 28.7,11.56 28.96,11.3 28.96,9.91 28.45,9.4 v28.45,9.17
P4.2  (via drill 0.3)
  Top 0.203: J1.17 7.62,13.97 7.62,11.92 7.98,11.56 10.92,11.56 13.21,9.27 17.65,9.27 18.16,8.76 26.92,8.76 27.43,9.27 27.69,9.53 v28.32,10.16 | v27.18,20.07 v27.18,23.11 | U6.47 35.15,23.65 34.77,24.03 v34.19,24.03
  Bottom 0.203: v27.18,20.07 28.32,18.92 v28.32,10.16 | v27.18,23.11 27.43,23.37 33.53,23.37 v34.19,24.03
P4.3  (via drill 0.3)
  Top 0.203: U6.48 37.11,24.15 37.9,23.37 39.42,23.37 39.88,22.91 39.88,21.01 40.06,20.83 v40.26,20.83 | v46.79,21.08 48.77,21.08 J5.13
  Bottom 0.203: v46.79,21.08 46.61,21.21 42.16,21.21 41.78,20.83 v40.26,20.83
P4.4/UCA1TXD  (via drill 0.3)
  Top 0.203: U6.51 36.06,25.63 37.54,25.63 40.11,28.19 40.89,28.19 41.78,29.08 v41.78,29.21 | v42.44,31.9 42.8,32.26 42.8,44.07 JP6.1.2
  Bottom 0.203: v41.78,29.21 42.29,29.72 42.29,31.75 v42.44,31.9
P4.5/UCA1RXD  (via drill 0.3)
  Top 0.203: U6.52 36.05,26.16 37.47,26.16 39.88,28.57 40.51,28.57 40.77,28.83 v40.77,29.44 | v41.78,32.64 42.42,33.27 42.42,45.21 JP6.2.2
  Bottom 0.203: v41.78,32.64 41.78,30.45 v40.77,29.44
P4.7  (via drill 0.3)
  Top 0.203: U6.54 34.9,27.15 34.67,26.92 34.67,25.4 v34.29,25.02 | v30.35,9.02 30.35,7.75 31.24,6.86 34.29,6.86 34.92,6.22 R30.1 | v28.32,24.38 28.45,24.38 29.59,23.24 v29.59,20.83
  Bottom 0.203: v29.59,20.83 29.84,20.57 29.84,19.56 29.46,19.18 29.46,13.59 30.35,12.7 30.35,10.67 30.61,10.41 30.61,9.27 v30.35,9.02 | v28.32,24.38 28.57,24.13 31.75,24.13 33.02,25.4 33.91,25.4 v34.29,25.02
P5.2/XT2IN
  Top 0.203: U6.69 29.96,34.15 28.88,35.23 Q4.3
P5.3/XT2OUT
  Top 0.203: Q4.1 25.88,35.33 26.44,34.77 28.63,34.77 29.46,33.93 U6.70
P5.4/XIN
  Top 0.203: U6.12 19.37,24.65 18.92,24.21 16.43,24.21 16.04,23.81 Q2.P2 14.78,21.84 C26.2
P5.5/XOUT
  Top 0.203: C25.2 18.22,21.86 Q2.P1 | Q2.P1 17.03,23.1 | U6.13 20.95,24.16 20.09,23.29 17.17,23.29 Q2.P1
P6.0
  Top 0.203: U6.77 25.96,33.3 25.17,34.09 16.28,34.09 12.93,30.73 10.03,30.73 9.78,30.48 J1.6
P6.1
  Top 0.203: U6.78 25.46,33.19 24.97,33.68 16.54,33.68 10.79,27.94 J1.8
P6.2
  Top 0.203: U6.79 24.96,33.05 24.74,33.27 16.76,33.27 J1.10
P6.3
  Top 0.203: U6.80 24.09,32.23 23.44,32.87 17.02,32.87 10.03,25.88 10.03,24 J1.12
P6.4
  Top 0.203: J1.14 10.44,21.87 10.44,25.63 15.8,30.99 20.83,30.99 21.67,30.15 U6.1
P6.5  (via drill 0.3)
  Top 0.203: v12.7,34.29 10.03,34.29 v9.91,34.16 | U6.2 21.4,29.65 20.7,30.35 v17.27,30.35
  Bottom 0.203: v9.91,34.16 9.78,34.29 6.73,34.29 6.35,33.91 J1.3 | v12.7,34.29 13.72,34.29 14.73,33.27 16,33.27 16.51,32.77 16.51,31.11 v17.27,30.35
P6.6  (via drill 0.3, 0.3 pad 0.66)
  Top 0.203: v11.05,29.21 8.52,29.21 7.49,28.19 7.49,23.6 6.75,22.86 J1.11 | U6.3 21.14,29.15 20.63,29.66 15.75,29.66 v15.62,29.79
  Bottom 0.203: v15.62,29.79 11.62,29.79 v11.05,29.21
P6.7  (via drill 0.3 pad 0.3, 0.3 pad 0.66)
  Top 0.203: U6.4 32.64,28.65 v33.25,29.26 | v41.07,31.88 40.64,32.33 40.64,41.94 JP6.4.2 | v39.8,29.21 38.1,29.21 v37.97,29.34
  Bottom 0.203: v41.07,31.88 41.07,30.66 39.8,29.39 v39.8,29.21 | 33.25,29.23 v33.25,29.26 33.58,29.59 37.72,29.59 v37.97,29.34
P7.0
  Top 0.203: J1.16 10.92,19.81 10.92,25.53 14.48,29.08 20.45,29.08 21.38,28.15 U6.5
P7.4  (via drill 0.3)
  Top 0.203: v40.39,27.3 41.66,27.3 v42.04,26.92 | v45.97,26.8 46.1,26.92 51.05,26.92 J5.8 | U6.57 37.67,28.65 38.15,28.17 v38.15,27.76
  Bottom 0.203: v42.04,26.92 42.16,26.8 v45.97,26.8 | v40.39,27.3 38.61,27.3 v38.15,27.76
P8.1
  Top 0.203: U6.16 23.51,22.65 24,22.16 24,15.75 26.42,13.34 26.42,12.57 27.3,11.68 29.97,11.68 31.37,13.08 43.94,13.08 44.83,13.97 50.8,13.97 J5.20
P8.2
  Top 0.203: U6.17 23.31,22.15 23.62,21.84 23.62,15.49 25.91,13.21 25.91,12.45 27.05,11.3 30.23,11.3 31.62,12.7 J5.19
RST/SBWTDIO  (via drill 0.3, 0.3 pad 0.66)
  Top 0.203: v32,29.29 31.93,29.21 29.57,29.21 27.81,30.96 26.77,30.96 26.46,31.27 U6.76 26.46,33.41 25.38,34.49 17.96,34.49 v15.57,36.88 | R27.1 12.01,42.52 S3.2 | R27.1 14.39,42.39 15.11,42.39 15.57,41.94 v15.57,39.9 | C17.1 14.26,43.48 R27.1 | 42.42,30.23 43.56,31.37 43.56,39.5 46.99,42.93 JP4.2.2 | 42.42,30.23 v37.54,30.23 | J5.10 51.05,26.42 46.74,26.42 v46.23,25.91 | 42.42,30.23 42.8,29.84 42.8,26.42 v42.49,26.11
  Bottom 0.203: v15.57,39.9 v15.57,36.88 | v42.49,26.11 42.8,26.42 45.34,26.42 45.85,25.91 v46.23,25.91 | v37.54,30.23 37.21,30.23 36.96,29.97 32.69,29.97 v32,29.29
TARGET_DM
  Top 0.203: U6.64 32.46,34.26 32.97,34.77 32.97,37.8 31.98,38.79 29.13,38.79 24.75,43.16 C24.1 R31.2
TARGET_DP
  Top 0.203: 33.43,32.26 U6.62 33.46,37.89 32.16,39.19 29.45,39.19 26.56,42.08 | R32.2 C23.1 25.97,42.67 26.56,42.08 | R15.2 27.11,42.08 26.56,42.08
TARGET_PUR  (via drill 0.3 pad 0.66)
  Top 0.203: U6.63 32.97,32.22 32.97,31.22 33.07,31.11 34.44,31.11 35.51,32.18 35.51,32.77 33.86,34.42 33.86,38.15 32.41,39.6 29.79,39.6 28.36,41.03 R15.1 | R14.2 24.51,40.36 R16.2 25.4,41.2 v25.68,41.2 | R15.1 28.3,41.55 | v28.27,43.13 28.5,42.9 28.5,41.63 R15.1
  Bottom 0.203: v25.68,41.2 27.66,43.18 28.22,43.18 v28.27,43.13
TARGET_VUSB
  Top 0.203: U6.66 31.46,35.04 C16.1
TEST/SBWTCK  (via drill 0.3, 0.3 pad 0.66)
  Top 0.203: U6.71 28.96,30.65 29.84,29.77 31.06,29.77 v31.55,30.25 | v36.4,30.91 42.49,30.91 43.18,31.6 43.18,40.13 v45.85,42.8 | v48.06,42.8 49.53,44.27 JP4.1.2
  Bottom 0.203: v36.4,30.91 35.84,30.35 32.38,30.35 32.28,30.25 v31.55,30.25 | v45.85,42.8 v48.06,42.8
V18
  Top 0.203: C15.1 30.96,35.22 U6.67
VCORE
  Top 0.305: C18.2 U6.20

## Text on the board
tDocu: USB Hub | eZ-FET lite | LaunchPad | GND | RST | 5V | 3V3 | RTS >> | CTS << | RXD << | TXD >> | SBW RST | SBW TST | Rev1.5 | MSP-EXP430F5529LP | BSL | 3V3 | P2.5 | 5V | GND | P6.5 | P2.4 | GND | P2.0 | P3.4 | P1.5 | P6.0 | P2.2 | P3.3 | P1.4 | P6.1 | P7.4 | P1.6 | P1.3 | P6.2 | RST | P6.6 | P1.2 | P6.3 | P3.0 | P3.2 | P4.3 | P6.4 | P3.1 | P2.7 | P4.0 | P7.0 | P2.6 | P4.2 | P3.7 | P3.6 | P2.3 | P4.1 | P8.2 | P3.5 | P8.1 | GND | P1.1 | P2.1 | GND | GND | P1.0 | P4.7 | GND | 5V | 3V3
